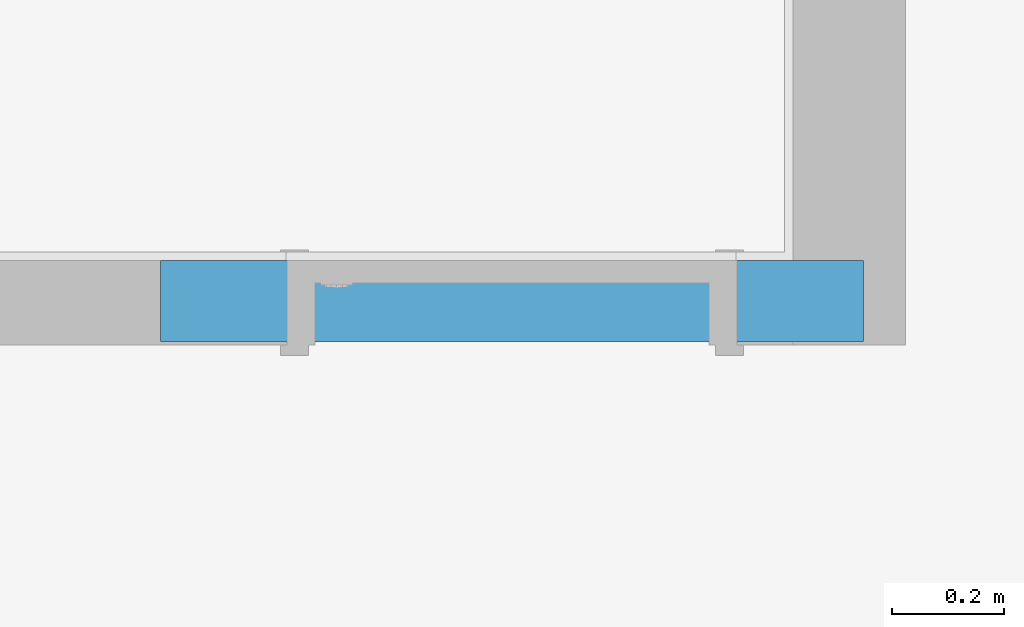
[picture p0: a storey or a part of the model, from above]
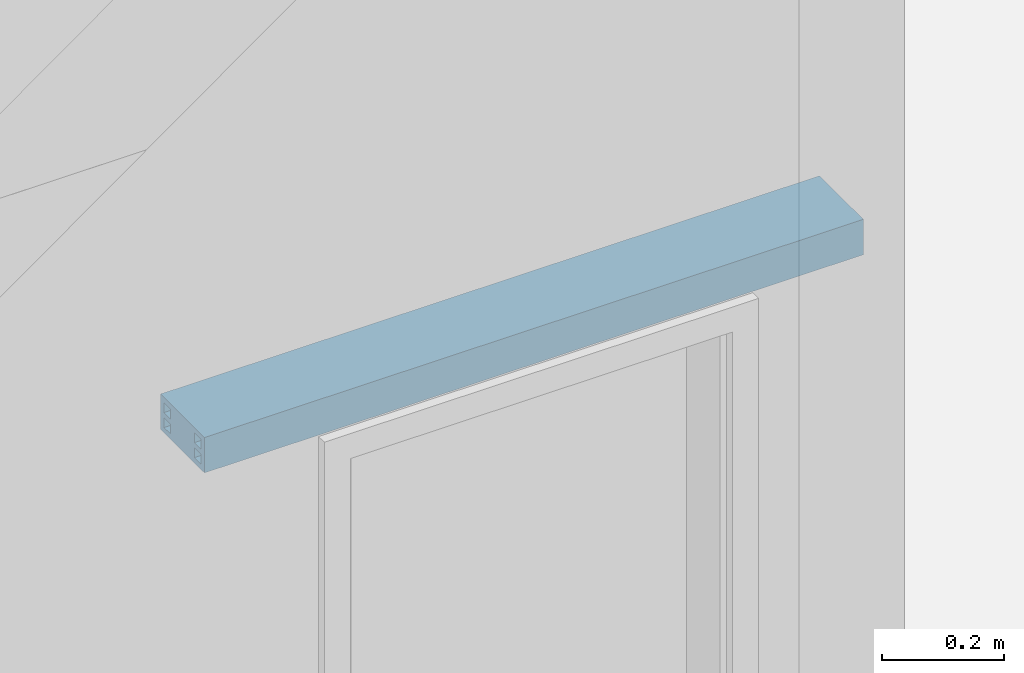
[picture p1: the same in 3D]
Properties of the parts of a building model (IFC4)

# File
Description: ViewDefinition [ReferenceView_V1.2], ExchangeRequirement [Architecture], Option [Elements to export: Visible elements (on all stories)], Option [Partial Structure Display: Entire Model], Option [IFC Domain: All], Option [Structural Function: All Elements], Option [Convert Grid elements: On], Option [Convert IFC Annotations and Archicad 2D elements: Off], Option [Convert 2D symbols of Doors and Windows: Off], Option [Export geometries that Participates in Collision Detection only: On], Option [Split complex elements: Off], Option [Material Preservation: Explode where necessary], Option [IFC Model position: Survey Point and Project Origin], Option [Curtain Wall export mode: Single Element], Option [Railing export mode: Single Element], Option [Stair export mode: Single Element], Option [Properties To Export: All properties], Option [Space containment: On], Option [IFC Domain For Space Containment: All], Option [Geometry to type objects: Off], Option [Element Properties: Off], Option [Building Material Properties: Off], Option [Element Parameters: Off], Option [Component Parameters: Off], Option [IFC Base Quantities: On], Option [Door Window Parameters: On], Option [IFC Space boundaries: On], Option [Archicad Zone Categories as IFC Space classification data: Off], Option [Element Classifications: Off]
File name: C:\Users\micel\OneDrive\Dokumenty\ŠKOLA\!!4.LS!!\BAKALÁŘKA\Publikace\Nová složka\LES24-PST-ZZ-M3-Nenosne_kce_podlahy.ifc
Time: 2024-05-22T15:32:19
Author: Architect
Organization: Building Designer Office
Written by: DDS_IFC v3.0
Made in: IFC file generated by Graphisoft Archicad 27.0.0 CZE FULL Windows version (IFC add-on version: 3001 CZE FULL).
Authorization: The authorising person

# IfcProject, Univerzitní lezecké centrum
Description: BIM projekt - bakalářská práce

# IfcSite, Exteriér
RefLatitude: 50, 1, 18, 339575; RefLongitude: 15, 46, 11, 568244; RefElevation: 221783 mm
Qto_SiteBaseQuantities - GrossPerimeter: 0 mm; GrossArea: 3562 m2

# IfcBuilding, Univerzitní lezecké centrum
Qto_BuildingBaseQuantities - GrossFloorArea: 0 m2

# IfcBuildingStorey (5)
In: Univerzitní lezecké centrum
Qto_BuildingStoreyBaseQuantities - GrossFloorArea: 0 m2
Name | Elevation (mm) | NetHeight (mm) = GrossHeight (mm)
2.NP | 3200 | 3200
4.NP | 9600 | 3200
1.NP | 0 | 3200
1.PP | -3350 | 3350
3.NP | 6400 | 3200

# IfcBeam: PTH Překlad KP 11,5 a 14,5 (15)
Type - PredefinedType: BEAM
Pset_BeamCommon - Status: EXISTING
Pset_ManufacturerOccurrence - AcquisitionDate: DD.MM.RRRR
Name | In | IsExternal | LoadBearing
2 x Pk02 | 1.PP
3 x Pk01 | 1.PP
Pk01 | 1.NP
2 x Pk02 | 2.NP | no | yes
6 x Pk01 | 2.NP | no | yes
Pk01 | 4.NP

# IfcBeam: PTH Překlad KP7 (3)
Type - PredefinedType: BEAM
Pset_ManufacturerOccurrence - AcquisitionDate: DD.MM.RRRR
Pset_BeamCommon - Status: EXISTING; LoadBearing: yes
Name | In
2 x Pk03 | 1.PP
Pk03 | 1.NP

# IfcDoor: Dveře 24 (8)
Type - OperationType: SINGLE_SWING_LEFT
Type - Door Lining Properties - LiningThickness: 50 mm; CasingThickness: 50 mm; CasingDepth: 19 mm
Type - Door Panel Properties - Panel 1 - PanelDepth: 40 mm; PanelOperation: SWINGING; PanelWidth: 1; PanelPosition: MIDDLE
Parametry - Kování: Bezpečnostní kování; Lakované - RAL 9007; Zámek - fab vložka, stavitelné panty, klika; Typ zárubně: Obložková zárubeň, RAL 6019; Prosklení: Plné (bez prosklení); Materiál dveřního křídla: Dřevěné (dýhované), lakované RAL 6019
Pset_DoorCommon - ThermalTransmittance: 0; Status: EXISTING
Pset_ManufacturerOccurrence - AcquisitionDate: DD.MM.RRRR
Name | In | OverallHeight (mm) | OverallWidth (mm) | Požární odolnost | Tloušťka rámu | Height (mm) | Width (mm) | Perimeter (mm) | Area (m2)
D19 | 1.PP | 2020 | 800 | Bez požadavku | 200 | 0 | 0 | 0 | 0
D05 | 1.PP | 2020 | 800 | Bez požadavku | 150 | 2020 | 800 | 5640 | 1.616
D08 | 1.PP | 2020 | 1000 | Bez požadavku | 150 | 2020 | 1000 | 6040 | 2.02
D11 | 1.NP | 2020 | 900 | EI 30 DP1 - C | 200 | 2020 | 900 | 5840 | 1.818
D14 | 2.NP | 2150 | 800 | Bez požadavku | 150 | 0 | 0 | 0 | 0
2 x D05 | 2.NP | 2020 | 800 | Bez požadavku | 150 | 0 | 0 | 0 | 0
D18 | 2.NP | 2020 | 1000 | Bez požadavku | 150 | 2020 | 1000 | 6040 | 2.02

# IfcDoor: Dveře 24 (10)
Type - OperationType: SINGLE_SWING_RIGHT
Type - Door Lining Properties - LiningThickness: 50 mm; CasingThickness: 50 mm; CasingDepth: 19 mm
Type - Door Panel Properties - Panel 1 - PanelDepth: 40 mm; PanelOperation: SWINGING; PanelWidth: 1; PanelPosition: MIDDLE
Parametry - Kování: Bezpečnostní kování; Lakované - RAL 9007; Zámek - fab vložka, stavitelné panty, klika; Typ zárubně: Obložková zárubeň, RAL 6019; Prosklení: Plné (bez prosklení); Materiál dveřního křídla: Dřevěné (dýhované), lakované RAL 6019; Požární odolnost: Bez požadavku
Pset_DoorCommon - ThermalTransmittance: 0; Status: EXISTING
Pset_ManufacturerOccurrence - AcquisitionDate: DD.MM.RRRR
Name | In | OverallHeight (mm) | OverallWidth (mm) | Tloušťka rámu | Height (mm) | Width (mm) | Perimeter (mm) | Area (m2)
D07 | 1.PP | 2020 | 1000 | 150 | 0 | 0 | 0 | 0
2 x D06 | 1.PP | 2020 | 800 | 150 | 0 | 0 | 0 | 0
D20 | 1.PP | 2020 | 800 | 200 | 2020 | 800 | 5640 | 1.616
D06 | 1.NP | 2020 | 800 | 150 | 2020 | 800 | 5640 | 1.616
D17 | 2.NP | 2020 | 1000 | 150 | 2020 | 1000 | 6040 | 2.02
2 x D06 | 2.NP | 2020 | 800 | 150 | 0 | 0 | 0 | 0
D14 | 2.NP | 2150 | 800 | 150 | 2150 | 800 | 5900 | 1.72
D06 | 4.NP | 2020 | 800 | 150 | 2020 | 800 | 5640 | 1.616

# IfcFurniture: Keramické tvárnice nenosné tl. 150 mm 230
In: 1.NP
Description: Deska recepčního pultu; Material: Keramické tvárnice nenosné tl. 150 mm
Pset_ManufacturerOccurrence - AcquisitionDate: DD.MM.RRRR

# IfcOpeningElement (18)
Name | In | Depth (mm) | Height (mm) | Width (mm) | Area (m2) | Volume (m3)
D19 | 1.PP | 200 | 0 | 0 | 0 | 0.111782
D07 | 1.PP | 150 | 0 | 0 | 0 | 0.117572
D06 | 1.PP | 150 | 0 | 0 | 0 | 0.100082
D06 | 1.PP | 150 | 0 | 0 | 0 | 0.0999325
D05 | 1.PP | 150 | 2020 | 800 | 1.616 | 0.0999325
D08 | 1.PP | 150 | 2020 | 1000 | 2.02 | 0.117572
D20 | 1.PP | 200 | 2020 | 800 | 1.616 | 0.111782
D11 | 1.NP | 200 | 2020 | 900 | 1.818 | 0.120852
D06 | 1.NP | 150 | 2020 | 800 | 1.616 | 0.0999325
D17 | 2.NP | 150 | 2020 | 1000 | 2.02 | 0.117572
D14 | 2.NP | 150 | 0 | 0 | 0 | 0.104041
2 x D05 | 2.NP | 150 | 0 | 0 | 0 | 0.0999325
2 x D06 | 2.NP | 150 | 0 | 0 | 0 | 0.0999325
D14 | 2.NP | 150 | 2150 | 800 | 1.72 | 0.104041
D18 | 2.NP | 150 | 2020 | 1000 | 2.02 | 0.117572
D06 | 4.NP | 150 | 2020 | 800 | 1.616 | 0.0999325

# IfcSlab: !Okapový chodník/Terasa/chodník 312
In: 1.NP
Type - PredefinedType: ROOF
Material: Betonová dlažba zámková, Štěrk - frakce 4/8, Štěrk - frakce 8/16, Geotextilie 300 g/m2
Pset_SlabCommon - Status: EXISTING; LoadBearing: yes
Pset_ManufacturerOccurrence - AcquisitionDate: DD.MM.RRRR
Qto_SlabBaseQuantities - Width: 312 mm; Perimeter: 13.8539 mm; GrossArea: 0.00000555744 m2; NetArea: 0.00000555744 m2; GrossVolume: 0.00000173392 m3; NetVolume: 0.00000173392 m3; Betonová dlažba zámková, Width: 60 mm; Štěrk - frakce 4/8, Width: 40 mm; Štěrk - frakce 8/16, Width: 160 mm; Geotextilie 300 g/m2, Width: 2 mm

# IfcSlab: !P01 Podlaha na terénu - keramická dlažba 30x30 220, P01
In: 1.PP
Type - PredefinedType: FLOOR
Material: Keramická dlažba 30x30, Lepicí tmel na dlažbu a obklady, Samonivelační stěrková hmota, Hydroizolace - stěrková hmota, Penetrační nátěr, Betonová mazanina, PE fólie, Tepelná izolace - polystyren EPS podlahy, Hydroizolace - modifikovaný asfaltový pás, Penetrační nátěr asfaltový
Pset_SlabCommon - Status: EXISTING; LoadBearing: yes
Pset_ManufacturerOccurrence - AcquisitionDate: DD.MM.RRRR
Qto_SlabBaseQuantities - Width: 219.5 mm; Perimeter: 58727.6 mm; GrossArea: 144.231 m2; NetArea: 135.277 m2; GrossVolume: 31.8491 m3; NetVolume: 29.8836 m3; Keramická dlažba 30x30, Width: 10 mm; Lepicí tmel na dlažbu a obklady, Width: 3 mm; Samonivelační stěrková hmota, Width: 3 mm; Hydroizolace - stěrková hmota, Width: 2 mm; Penetrační nátěr, Width: 1 mm; Betonová mazanina, Width: 75 mm; PE fólie, Width: 0.5 mm; Tepelná izolace - polystyren EPS podlahy, Width: 120 mm; Hydroizolace - modifikovaný asfaltový pás, Width: 4 mm; Penetrační nátěr asfaltový, Width: 1 mm

# IfcSlab: !P02 Podlaha na terénu - keramická dlažba 60x60 220 (2)
In: 1.PP
Type - PredefinedType: FLOOR
Material: Keramická dlažba 60x60, Lepicí tmel na dlažbu a obklady, Samonivelační stěrková hmota, Hydroizolace - stěrková hmota, Penetrační nátěr, Betonová mazanina, PE fólie, Tepelná izolace - polystyren EPS podlahy, Hydroizolace - modifikovaný asfaltový pás, Penetrační nátěr asfaltový
Pset_ManufacturerOccurrence - AcquisitionDate: DD.MM.RRRR
Pset_SlabCommon - Status: EXISTING
Qto_SlabBaseQuantities - Width: 219.5 mm; Keramická dlažba 60x60, Width: 10 mm; Lepicí tmel na dlažbu a obklady, Width: 3 mm; Samonivelační stěrková hmota, Width: 3 mm; Hydroizolace - stěrková hmota, Width: 2 mm; Penetrační nátěr, Width: 1 mm; Betonová mazanina, Width: 75 mm; PE fólie, Width: 0.5 mm; Tepelná izolace - polystyren EPS podlahy, Width: 120 mm; Hydroizolace - modifikovaný asfaltový pás, Width: 4 mm; Penetrační nátěr asfaltový, Width: 1 mm
Name | Perimeter (mm) | GrossArea (m2) | NetArea (m2) | GrossVolume (m3) | NetVolume (m3)
P02 | 17770.6 | 9.21407 | 8.33584 | 2.02233 | 1.82956 | Pset_SlabCommon - LoadBearing: yes
P02 | 14831.3 | 14.3689 | 14.1468 | 3.15396 | 3.10522 | Pset_SlabCommon - IsExternal: no

# IfcSlab: !P03 Podlaha v patře - keramická dlažba 60x60 120 (4)
Type - PredefinedType: FLOOR
Material: Keramická dlažba 60x60, Lepicí tmel na dlažbu a obklady, Samonivelační stěrková hmota, Betonová mazanina, PE fólie, Akustická izolace - EPS
Pset_SlabCommon - Status: EXISTING; LoadBearing: yes
Pset_ManufacturerOccurrence - AcquisitionDate: DD.MM.RRRR
Qto_SlabBaseQuantities - Width: 119.5 mm; Keramická dlažba 60x60, Width: 10 mm; Lepicí tmel na dlažbu a obklady, Width: 3 mm; Samonivelační stěrková hmota, Width: 3 mm; Betonová mazanina, Width: 63 mm; PE fólie, Width: 0.5 mm; Akustická izolace - EPS, Width: 40 mm
Name | In | Perimeter (mm) | GrossArea (m2) | NetArea (m2) | GrossVolume (m3) | NetVolume (m3)
P03 | 1.NP | 54495.8 | 152.616 | 148.791 | 18.2376 | 17.7806
P03 | 2.NP | 15181.6 | 14.247 | 14.1612 | 1.70252 | 1.69226
P03 | 3.NP | 40740.1 | 31.2389 | 31.2389 | 3.73305 | 3.73304
P03 | 4.NP | 45092.5 | 63.2084 | 62.2234 | 7.55341 | 7.43569

# IfcSlab: !P04 Podlaha v patře - keramická dlažba 30x30 120 (4)
Type - PredefinedType: FLOOR
Material: Keramická dlažba 30x30, Lepicí tmel na dlažbu a obklady, Samonivelační stěrková hmota, Betonová mazanina, PE fólie, Akustická izolace - EPS
Pset_SlabCommon - Status: EXISTING; LoadBearing: yes
Qto_SlabBaseQuantities - Width: 119.5 mm; Keramická dlažba 30x30, Width: 10 mm; Lepicí tmel na dlažbu a obklady, Width: 3 mm; Samonivelační stěrková hmota, Width: 3 mm; Betonová mazanina, Width: 63 mm; PE fólie, Width: 0.5 mm; Akustická izolace - EPS, Width: 40 mm
Pset_ManufacturerOccurrence - AcquisitionDate: DD.MM.RRRR
Name | In | Perimeter (mm) | GrossArea (m2) | NetArea (m2) | GrossVolume (m3) | NetVolume (m3)
P03 | 1.NP | 15785.6 | 12.3424 | 12.3422 | 1.47491 | 1.4749
P03 | 1.NP | 6549.48 | 2.55715 | 2.55715 | 0.305579 | 0.305579
P04 | 2.NP | 21385.9 | 28.0574 | 26.6548 | 3.35286 | 3.18525
P04 | 2.NP | 21415.9 | 28.0724 | 26.6698 | 3.35465 | 3.18704

# IfcSlab: !Podlaha na terénu - polyuretanová stěrka 220, P06
In: 1.PP
Type - PredefinedType: FLOOR
Material: Polyuretanová stěrka - sport, Penetrační nátěr pod polyuretanovou stěrku, Samonivelační stěrková hmota, Betonová mazanina, PE fólie, Tepelná izolace - polystyren EPS podlahy, Hydroizolace - modifikovaný asfaltový pás, Penetrační nátěr asfaltový
Pset_SlabCommon - Status: EXISTING; LoadBearing: yes
Pset_ManufacturerOccurrence - AcquisitionDate: DD.MM.RRRR
Qto_SlabBaseQuantities - Width: 219.5 mm; Perimeter: 51417.3 mm; GrossArea: 156.982 m2; NetArea: 154.317 m2; GrossVolume: 34.4575 m3; NetVolume: 33.8726 m3; Polyuretanová stěrka - sport, Width: 1 mm; Penetrační nátěr pod polyuretanovou stěrku, Width: 1 mm; Samonivelační stěrková hmota, Width: 3 mm; Betonová mazanina, Width: 89 mm; PE fólie, Width: 0.5 mm; Tepelná izolace - polystyren EPS podlahy, Width: 120 mm; Hydroizolace - modifikovaný asfaltový pás, Width: 4 mm; Penetrační nátěr asfaltový, Width: 1 mm

# IfcSlab: !Podlaha v patře - polyuretanová stěrka - sport 120, P05a
In: 2.NP
Type - PredefinedType: FLOOR
Material: Polyuretanová stěrka - sport, Penetrační nátěr pod polyuretanovou stěrku, Samonivelační stěrková hmota, Betonová mazanina, PE fólie, Akustická izolace - EPS
Qto_SlabBaseQuantities - Width: 119.5 mm; Perimeter: 41289.7 mm; GrossArea: 91.0404 m2; NetArea: 89.2593 m2; GrossVolume: 10.8793 m3; NetVolume: 10.6665 m3; Polyuretanová stěrka - sport, Width: 1 mm; Penetrační nátěr pod polyuretanovou stěrku, Width: 1 mm; Samonivelační stěrková hmota, Width: 3 mm; Betonová mazanina, Width: 74 mm; PE fólie, Width: 0.5 mm; Akustická izolace - EPS, Width: 40 mm
Pset_ManufacturerOccurrence - AcquisitionDate: DD.MM.RRRR
Pset_SlabCommon - Status: EXISTING; LoadBearing: yes

# IfcSlab: !Podlaha v patře - polyuretanová stěrka 120 (2)
In: 3.NP
Type - PredefinedType: FLOOR
Material: Polyuretanová stěrka, Penetrační nátěr pod polyuretanovou stěrku, Samonivelační stěrková hmota, Betonová mazanina, PE fólie, Akustická izolace - EPS
Qto_SlabBaseQuantities - Width: 119.5 mm; Polyuretanová stěrka, Width: 1 mm; Penetrační nátěr pod polyuretanovou stěrku, Width: 1 mm; Samonivelační stěrková hmota, Width: 3 mm; Betonová mazanina, Width: 74 mm; PE fólie, Width: 0.5 mm; Akustická izolace - EPS, Width: 40 mm
Pset_SlabCommon - Status: EXISTING; LoadBearing: yes
Pset_ManufacturerOccurrence - AcquisitionDate: DD.MM.RRRR
Name | Perimeter (mm) | GrossArea (m2) | NetArea (m2) | GrossVolume (m3) | NetVolume (m3)
P05b | 18894.6 | 13.0671 | 13.0467 | 2.59749 | 2.59505
P03 | 19786.7 | 23.467 | 23.467 | 2.8043 | 2.8043

# IfcSlab: !SDK - hygienický 90 (11)
Type - PredefinedType: FLOOR
Description: Sádrokartonový podhled - hygienický, SDK desky se zvýšenou odolností do vlhka, na samonosném roštu; Material: SDK - UA profil nosný 50, SDK - R-CD profil montážní, Sádrokarton - voděodolný
Pset_SlabCommon - Status: EXISTING; LoadBearing: yes
Pset_ManufacturerOccurrence - AcquisitionDate: DD.MM.RRRR
Qto_SlabBaseQuantities - Width: 90 mm; SDK - UA profil nosný 50, Width: 50 mm; SDK - R-CD profil montážní, Width: 27 mm; Sádrokarton - voděodolný, Width: 13 mm
Name | In | Perimeter (mm) | GrossArea (m2) | NetArea (m2) | GrossVolume (m3) | NetVolume (m3)
Pdh01 | 1.PP | 15699.4 | 9.41867 | 9.41867 | 0.84768 | 0.84768
2 x Pdh01 | 1.PP | 14299.5 | 11.9238 | 11.9238 | 1.07314 | 1.07314
Pdh01 | 1.PP | 15856.7 | 9.53889 | 9.4189 | 0.8585 | 0.847701
Pdh01 | 1.PP | 7099.48 | 3.14456 | 2.58964 | 0.327404 | 0.277461
2 x Pdh01 | 2.NP | 8009.59 | 3.99911 | 3.98961 | 0.35992 | 0.359065
Pdh01 | 2.NP | 6099.58 | 1.99479 | 1.99468 | 0.179531 | 0.179521
Pdh01 | 2.NP | 8699.04 | 4.72396 | 4.09391 | 0.425157 | 0.368452
Pdh01 | 2.NP | 6099.58 | 1.99479 | 1.99464 | 0.179531 | 0.179518
Pdh01 | 2.NP | 8699 | 4.72391 | 4.09383 | 0.425152 | 0.368445

# IfcSlab: !SDK - protipožární 152 (2)
In: 4.NP
Type - PredefinedType: FLOOR
Description: Sádrokartonový podhled - protipožární, SDK deska se zvýšenou odolností a stabilitou při požáru, na samonosném roštu; Material: SDK - UA profil nosný 50, SDK - R-CD profil montážní, Sádrokarton - protipožární spodní, Sádrokarton - protipožární vrchní
Pset_SlabCommon - Status: EXISTING; LoadBearing: yes
Pset_ManufacturerOccurrence - AcquisitionDate: DD.MM.RRRR
Qto_SlabBaseQuantities - Width: 152 mm; SDK - UA profil nosný 50, Width: 100 mm; SDK - R-CD profil montážní, Width: 27 mm; Sádrokarton - protipožární spodní, Width: 12 mm; Sádrokarton - protipožární vrchní, Width: 13 mm
Name | Perimeter (mm) | GrossArea (m2) | NetArea (m2) | GrossVolume (m3) | NetVolume (m3)
Pdh02 | 19786.3 | 23.2636 | 22.7836 | 3.53606 | 3.46311
Pdh02 | 19786.4 | 24.0737 | 24.0737 | 3.65921 | 3.65921

# IfcSlab: Beton zákad pod technická zařízení 150 (2)
In: 3.NP
Type - PredefinedType: FLOOR
Description: Betonový základ pro technologii ohřevu vody; Material: Beton zákad pod technická zařízení
Pset_SlabCommon - IsExternal: no; Status: EXISTING
Pset_ManufacturerOccurrence - AcquisitionDate: DD.MM.RRRR
Qto_SlabBaseQuantities - Width: 150 mm; Beton zákad pod technická zařízení, Width: 150 mm
Name | Perimeter (mm) | GrossArea (m2) = NetArea (m2) | GrossVolume (m3) = NetVolume (m3)
 | 12933.8 | 7.32782 | 1.09917
 | 5900 | 1.72 | 0.258

# IfcSlab: Keramická dlažba 20x40 - obklad 1500 (3)
Type - PredefinedType: FLOOR
Description: Keramický obklad, lepeno stavebním lepidlem, součástí skladeb přilehlých svislých konstrukcí; Material: Keramická dlažba 20x40 - obklad
Pset_SlabCommon - IsExternal: no; Status: EXISTING
Qto_SlabBaseQuantities - Width: 1500 mm; Keramická dlažba 20x40 - obklad, Width: 1500 mm
Pset_ManufacturerOccurrence - AcquisitionDate: DD.MM.RRRR
Name | In | Perimeter (mm) | GrossArea (m2) = NetArea (m2) | GrossVolume (m3) = NetVolume (m3)
 | 1.PP | 11906.6 | 0.0890746 | 0.133612
 | 1.NP | 11109 | 0.0830922 | 0.124638
 | 4.NP | 10509 | 0.0785922 | 0.117888

# IfcSlab: Keramická dlažba 20x40 - obklad 175 (2)
In: 2.NP
Type - PredefinedType: FLOOR
Description: Keramický obklad, lepeno stavebním lepidlem, součástí skladeb přilehlých svislých konstrukcí; Material: Keramická dlažba 20x40 - obklad
Pset_ManufacturerOccurrence - AcquisitionDate: DD.MM.RRRR
Qto_SlabBaseQuantities - Width: 175 mm; Perimeter: 1630 mm; GrossArea: 0.012 m2; NetArea: 0.012 m2; GrossVolume: 0.0021 m3; NetVolume: 0.0021 m3; Keramická dlažba 20x40 - obklad, Width: 175 mm
Pset_SlabCommon - IsExternal: no; Status: EXISTING

# IfcSlab: Keramická dlažba 20x40 - obklad 2300 (10)
Type - PredefinedType: FLOOR
Description: Keramický obklad, lepeno stavebním lepidlem, součástí skladeb přilehlých svislých konstrukcí; Material: Keramická dlažba 20x40 - obklad
Pset_SlabCommon - IsExternal: no; Status: EXISTING
Pset_ManufacturerOccurrence - AcquisitionDate: DD.MM.RRRR
Qto_SlabBaseQuantities - Width: 2300 mm; Keramická dlažba 20x40 - obklad, Width: 2300 mm
Name | In | Perimeter (mm) | GrossArea (m2) = NetArea (m2) | GrossVolume (m3) = NetVolume (m3)
2 x  | 1.PP | 29708.1 | 0.22261 | 0.512002
2 x  | 2.NP | 6669.2 | 0.049794 | 0.114526
2 x  | 2.NP | 349.985 | 0.00239989 | 0.00551975
2 x  | 2.NP | 15708.4 | 0.116827 | 0.268702
2 x  | 2.NP | 350 | 0.0024 | 0.00552

# IfcSlab: Keramická dlažba 20x40 - obklad 2600 (4)
Type - PredefinedType: FLOOR
Description: Keramický obklad, lepeno stavebním lepidlem, součástí skladeb přilehlých svislých konstrukcí; Material: Keramická dlažba 20x40 - obklad
Pset_ManufacturerOccurrence - AcquisitionDate: DD.MM.RRRR
Pset_SlabCommon - IsExternal: no; Status: EXISTING
Qto_SlabBaseQuantities - Width: 2600 mm; Keramická dlažba 20x40 - obklad, Width: 2600 mm
Name | In | Perimeter (mm) | GrossArea (m2) = NetArea (m2) | GrossVolume (m3) = NetVolume (m3)
2 x  | 1.PP | 26909 | 0.201592 | 0.52414
2 x  | 2.NP | 14309.2 | 0.107109 | 0.278484

# IfcSlab: Keramická dlažba 20x40 - obklad 275 (6)
In: 2.NP
Type - PredefinedType: FLOOR
Description: Keramický obklad, lepeno stavebním lepidlem, součástí skladeb přilehlých svislých konstrukcí; Material: Keramická dlažba 20x40 - obklad
Pset_SlabCommon - IsExternal: no; Status: EXISTING
Pset_ManufacturerOccurrence - AcquisitionDate: DD.MM.RRRR
Qto_SlabBaseQuantities - Width: 275 mm; Perimeter: 1630 mm; GrossArea: 0.012 m2; NetArea: 0.012 m2; GrossVolume: 0.0033 m3; NetVolume: 0.0033 m3; Keramická dlažba 20x40 - obklad, Width: 275 mm

# IfcSlab: Keramická dlažba 20x40 - obklad 300 (2)
In: 1.PP
Type - PredefinedType: FLOOR
Description: Keramický obklad, lepeno stavebním lepidlem, součástí skladeb přilehlých svislých konstrukcí; Material: Keramická dlažba 20x40 - obklad
Pset_ManufacturerOccurrence - AcquisitionDate: DD.MM.RRRR
Qto_SlabBaseQuantities - Width: 300 mm; Perimeter: 1630 mm; GrossArea: 0.012 m2; NetArea: 0.012 m2; GrossVolume: 0.0036 m3; NetVolume: 0.0036 m3; Keramická dlažba 20x40 - obklad, Width: 300 mm
Pset_SlabCommon - IsExternal: no; Status: EXISTING

# IfcSlab: Keramická dlažba 20x40 - obklad 575 (2)
In: 2.NP
Type - PredefinedType: FLOOR
Description: Keramický obklad, lepeno stavebním lepidlem, součástí skladeb přilehlých svislých konstrukcí; Material: Keramická dlažba 20x40 - obklad
Pset_SlabCommon - IsExternal: no; Status: EXISTING
Pset_ManufacturerOccurrence - AcquisitionDate: DD.MM.RRRR
Qto_SlabBaseQuantities - Width: 575 mm; Perimeter: 1630 mm; GrossArea: 0.012 m2; NetArea: 0.012 m2; GrossVolume: 0.0069 m3; NetVolume: 0.0069 m3; Keramická dlažba 20x40 - obklad, Width: 575 mm

# IfcSlab: Keramická dlažba 20x40 - obklad 600 (2)
In: 1.PP
Type - PredefinedType: FLOOR
Description: Keramický obklad, lepeno stavebním lepidlem, součástí skladeb přilehlých svislých konstrukcí; Material: Keramická dlažba 20x40 - obklad
Pset_SlabCommon - IsExternal: no; Status: EXISTING
Pset_ManufacturerOccurrence - AcquisitionDate: DD.MM.RRRR
Qto_SlabBaseQuantities - Width: 600 mm; Perimeter: 1630 mm; GrossArea: 0.012 m2; NetArea: 0.012 m2; GrossVolume: 0.0072 m3; NetVolume: 0.0072 m3; Keramická dlažba 20x40 - obklad, Width: 600 mm

# IfcWall: !Vnitřní keramická stěna 150 mm - nenosná 150 (12)
Description: Nenosné broušené keramické tvárnice, 497x140x249 mm, prováděno na maltu pro tenké spáry Profi; Material: Keramické tvárnice nenosné tl. 150 mm
Pset_WallCommon - Status: EXISTING; LoadBearing: yes
Pset_ManufacturerOccurrence - AcquisitionDate: DD.MM.RRRR
Qto_WallBaseQuantities - Width: 150 mm; GrossSideArea: 0 m2; NetSideArea: 0 m2; Keramické tvárnice nenosné tl. 150 mm, Width: 150 mm
Name | In | Length (mm) | Height (mm) | GrossFootprintArea (m2) = NetFootprintArea (m2) | GrossVolume (m3) | NetVolume (m3)
2 x St07 | 1.PP | 1950.16 | 3250 | 0.142524 | 0.940088 | 0.604088
Z061 | 1.PP | 1197.75 | 3250 | 0.0598379 | 0.574549 | 0.305749
Z061 | 1.PP | 5452.48 | 3186.65 | 0.791632 | 1.35927 | 1.35927
St07 | 2.NP | 395.988 | 3000 | 0.0594945 | 0.178484 | 0.178484
St07 | 2.NP | 3100.15 | 3000 | 0.300022 | 1.33945 | 1.01845
St07 | 2.NP | 3100.15 | 3000 | 0.450022 | 1.35007 | 1.02914
St07 | 2.NP | 396.03 | 3000 | 0.0595096 | 0.178529 | 0.178529
St07 | 3.NP | 375 | 3000 | 0.0675 | 0.2025 | 0.2025
St07 | 3.NP | 4400 | 3000 | 0.66 | 1.98 | 1.98
St07 | 3.NP | 1275 | 3000 | 0.18 | 0.54 | 0.54
St07 | 4.NP | 450 | 3577.84 | 0.0675 | 0.240428 | 0.240428

# IfcWall: !Vnitřní keramická stěna 150 mm - nenosná s omítkou 150 (6)
Description: Nenosné broušené keramické tvárnice, 497x140x249 mm, prováděno na maltu pro tenké spáry Profi; Material: Keramické tvárnice nenosné tl. 150 mm
Pset_WallCommon - Status: EXISTING; LoadBearing: yes
Pset_ManufacturerOccurrence - AcquisitionDate: DD.MM.RRRR
Qto_WallBaseQuantities - Width: 150 mm; Keramické tvárnice nenosné tl. 150 mm, Width: 150 mm
Name | In | Length (mm) | Height (mm) | GrossFootprintArea (m2) = NetFootprintArea (m2) | GrossSideArea (m2) = NetSideArea (m2) | GrossVolume (m3) = NetVolume (m3)
St08* | 1.PP | 1850 | 3250 | 0.255 | 2.7625 | 0.82875
St07 | 1.NP | 1524.98 | 2950 | 0.240001 | 2.077 | 0.623102
St07 | 1.NP | 1800.5 | 230 | 0.000935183 | 0 | 0.000215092
St07 | 1.NP | 374.872 | 2950 | 0.0449807 | 0.442318 | 0.132693
St08* | 2.NP | 2099.8 | 3000 | 0.314969 | 3.14969 | 0.944909
St08* | 2.NP | 2099.8 | 3000 | 0.314969 | 3.14969 | 0.944908

# IfcWall: !Vnitřní keramická stěna 150 mm - nenosná* 150 (13)
Description: Nenosné broušené keramické tvárnice, 497x140x249 mm, prováděno na maltu pro tenké spáry Profi; Material: Keramické tvárnice nenosné tl. 150 mm
Pset_WallCommon - Status: EXISTING; LoadBearing: yes
Pset_ManufacturerOccurrence - AcquisitionDate: DD.MM.RRRR
Qto_WallBaseQuantities - Width: 150 mm; GrossSideArea: 0 m2; NetSideArea: 0 m2; Keramické tvárnice nenosné tl. 150 mm, Width: 150 mm
Name | In | Length (mm) | Height (mm) | GrossFootprintArea (m2) = NetFootprintArea (m2) | GrossVolume (m3) | NetVolume (m3)
St07* | 1.PP | 2705.12 | 3250 | 0.270911 | 1.26091 | 0.992112
2 x St07* | 1.PP | 2074.74 | 3250 | 0.299961 | 0.974873 | 0.974873
St07* | 1.PP | 2605.12 | 3250 | 0.270861 | 1.26075 | 0.991947
St07* | 1.PP | 4310.84 | 3250 | 0.647349 | 2.09038 | 2.09038
St07* | 1.PP | 4385.84 | 3250 | 0.669801 | 2.16335 | 2.16335
St07* | 1.NP | 1450 | 2950 | 0.1425 | 0.587397 | 0.330627
St07* | 2.NP | 5549.61 | 3000 | 0.809942 | 2.41723 | 2.41723
St07* | 2.NP | 5549.61 | 3000 | 0.809942 | 2.41633 | 2.41633
St07* | 2.NP | 5549.61 | 3000 | 0.712442 | 2.47321 | 2.20279
St07* | 2.NP | 5549.61 | 3000 | 0.712442 | 2.47411 | 2.20369
St07* | 4.NP | 1275 | 3832.9 | 0.2025 | 0.736494 | 0.479754
St07* | 4.NP | 2074.74 | 3577.84 | 0.299961 | 1.06843 | 1.06843

# IfcWall: !Vnitřní keramická stěna 150 mm - nenosná** 150 (8)
Description: Nenosné broušené keramické tvárnice, 497x140x249 mm, prováděno na maltu pro tenké spáry Profi; Material: Keramické tvárnice nenosné tl. 150 mm
Pset_WallCommon - Status: EXISTING; LoadBearing: yes
Pset_ManufacturerOccurrence - AcquisitionDate: DD.MM.RRRR
Qto_WallBaseQuantities - Width: 150 mm; GrossSideArea: 0 m2; NetSideArea: 0 m2; Keramické tvárnice nenosné tl. 150 mm, Width: 150 mm
Name | In | Length (mm) | Height (mm) | GrossFootprintArea (m2) = NetFootprintArea (m2) | GrossVolume (m3) | NetVolume (m3)
2 x St07** | 1.PP | 1674.99 | 3250 | 0.2625 | 0.85312 | 0.85312
St07** | 1.PP | 2724.74 | 3250 | 0.397461 | 1.29175 | 1.29175
St07** | 1.PP | 2874.74 | 3250 | 0.442461 | 1.438 | 1.438
2 x St07** | 2.NP | 2249.9 | 3000 | 0.217486 | 1.0029 | 0.746103
2 x St07** | 2.NP | 2099.8 | 3000 | 0.194969 | 0.935355 | 0.678555

# IfcWall: !Vnitřní keramická stěna 200 mm - nenosná 200 (3)
Description: Nenosné broušené keramické tvárnice, 372x190x238 mm, prováděno na maltu M10; Material: Keramické tvárnice nenosné tl 200 mm
Pset_WallCommon - Status: EXISTING
Qto_WallBaseQuantities - Width: 200 mm; GrossSideArea: 0 m2; NetSideArea: 0 m2; Keramické tvárnice nenosné tl 200 mm, Width: 200 mm
Pset_ManufacturerOccurrence - AcquisitionDate: DD.MM.RRRR
Name | In | Length (mm) | Height (mm) | GrossFootprintArea (m2) = NetFootprintArea (m2) | GrossVolume (m3) | NetVolume (m3) | LoadBearing
St06 | 1.NP | 5549.82 | 2830 | 0.929967 | 3.14121 | 2.77761
St06 | 2.NP | 925.449 | 3000 | 0.200086 | 0.600198 | 0.600198 | yes
St06 | 2.NP | 925.448 | 3000 | 0.199886 | 0.599657 | 0.599657 | yes

# IfcWall: !Vnitřní keramická stěna 200 mm - nenosná* 200 (3)
Description: Nenosné broušené keramické tvárnice, 372x190x238 mm, prováděno na maltu M10; Material: Keramické tvárnice nenosné tl 200 mm
Pset_WallCommon - Status: EXISTING; LoadBearing: yes
Pset_ManufacturerOccurrence - AcquisitionDate: DD.MM.RRRR
Qto_WallBaseQuantities - Width: 200 mm; GrossSideArea: 0 m2; NetSideArea: 0 m2; Keramické tvárnice nenosné tl 200 mm, Width: 200 mm
Name | In | Length (mm) | Height (mm) | GrossFootprintArea (m2) = NetFootprintArea (m2) | GrossVolume (m3) | NetVolume (m3)
St06* | 1.PP | 8175 | 3250 | 1.49 | 5.29398 | 4.93558
St06* | 1.PP | 8250 | 3250 | 1.49 | 5.29398 | 4.93558
St06* | 1.NP | 1999.74 | 2950 | 0.429948 | 1.26835 | 1.26835

# IfcWall: !Vnitřní pŕobetonová stěna 200 mm - nenosná 200, St09
In: 4.NP
Description: Pŕobetonové tvárnice nenosné, na stavební lepidlo; Material: Pórobetonové tvárnice - nenosné
Pset_WallCommon - Status: EXISTING; LoadBearing: yes
Pset_ManufacturerOccurrence - AcquisitionDate: DD.MM.RRRR
Qto_WallBaseQuantities - Length: 6114.95 mm; Height: 1228.24 mm; Width: 200 mm; GrossFootprintArea: 1.22341 m2; NetFootprintArea: 1.22341 m2; GrossSideArea: 3.11455 m2; NetSideArea: 3.11455 m2; GrossVolume: 1.33133 m3; NetVolume: 1.33133 m3; Pórobetonové tvárnice - nenosné, Width: 200 mm

# IfcWall: Keramické tvárnice nenosné tl. 150 mm 150 (8)
Description: Nenosné broušené keramické tvárnice, 497x140x249 mm, prováděno na maltu pro tenké spáry Profi; Material: Keramické tvárnice nenosné tl. 150 mm
Pset_WallCommon - Status: EXISTING; LoadBearing: yes
Qto_WallBaseQuantities - Width: 150 mm; Keramické tvárnice nenosné tl. 150 mm, Width: 150 mm
Pset_ManufacturerOccurrence - AcquisitionDate: DD.MM.RRRR
Name | In | Length (mm) | Height (mm) | GrossFootprintArea (m2) = NetFootprintArea (m2) | GrossSideArea (m2) = NetSideArea (m2) | GrossVolume (m3) = NetVolume (m3)
 | 1.PP | 600 | 3250 | 0.09 | 1.95 | 0.2925
2 x St08 | 1.PP | 3450 | 3250 | 0.5175 | 11.2125 | 1.68188
 | 1.PP | 450 | 3250 | 0.0675 | 1.4625 | 0.219375
St08 | 1.NP | 1350 | 2950 | 0.2025 | 3.9825 | 0.597375
St07 | 1.NP | 3050 | 2950 | 0.4575 | 8.9975 | 1.34963
Z062 | 4.NP | 1200 | 712.904 | 0.18 | 0.702444 | 0.105367
St08 | 4.NP | 1200 | 3120 | 0.18 | 3.744 | 0.5616

# IfcWall: Pórobetonové tvárnice - nenosné 150, Z061
In: 1.PP
Description: Pŕobetonové tvárnice nenosné, na stavební lepidlo; Material: Pórobetonové tvárnice - nenosné
Pset_ManufacturerOccurrence - AcquisitionDate: DD.MM.RRRR
Qto_WallBaseQuantities - Length: 1194.21 mm; Height: 1862.5 mm; Width: 150 mm; GrossFootprintArea: 0.156769 m2; NetFootprintArea: 0.156769 m2; GrossSideArea: 1.71622 m2; NetSideArea: 1.71622 m2; GrossVolume: 0.257729 m3; NetVolume: 0.257729 m3; Pórobetonové tvárnice - nenosné, Width: 150 mm
Pset_WallCommon - Status: EXISTING; LoadBearing: yes

# IfcWall: Pórobetonové tvárnice - nenosné 300
In: 4.NP
Description: Pŕobetonové tvárnice nenosné, na stavební lepidlo; Material: Pórobetonové tvárnice - nenosné
Pset_ManufacturerOccurrence - AcquisitionDate: DD.MM.RRRR
Qto_WallBaseQuantities - Length: 5120 mm; Height: 267.655 mm; Width: 300 mm; GrossFootprintArea: 1.536 m2; NetFootprintArea: 1.536 m2; GrossSideArea: 1.20715 m2; NetSideArea: 1.20715 m2; GrossVolume: 0.362145 m3; NetVolume: 0.362145 m3; Pórobetonové tvárnice - nenosné, Width: 300 mm
Pset_WallCommon - Status: EXISTING; LoadBearing: yes

# IfcWall: SDK - instalační předstěna 150 (8)
Description: Instalační předstěna z dvojitého SDK opláštění, na hliníkovém roštu, SDk se zvýšenou odolností do vlhka
Pset_WallCommon - Status: EXISTING; LoadBearing: yes
Pset_ManufacturerOccurrence - AcquisitionDate: DD.MM.RRRR
Qto_WallBaseQuantities - Width: 150 mm; Keramická dlažba 20x40 - obklad, Width: 7 mm; Lepicí tmel na dlažbu a obklady, Width: 3 mm; SDK nosný rám, Width: 115 mm
Name | In | Material | Length (mm) | Height (mm) | GrossFootprintArea (m2) = NetFootprintArea (m2) | GrossSideArea (m2) = NetSideArea (m2) | GrossVolume (m3) = NetVolume (m3) | Sádrokarton - voděodolný 1, Width (mm) | Sádrokarton - voděodolný 2, Width (mm)
St08 | 1.PP | Keramická dlažba 20x40 - obklad, Lepicí tmel na dlažbu a obklady, Sádrokarton - voděodolný (2), SDK nosný rám | 2174.76 | 3049 | 0.314963 | 6.38221 | 0.959673 | 13 | 12
St08 | 1.PP | SDK nosný rám, Sádrokarton - voděodolný (2), Lepicí tmel na dlažbu a obklady, Keramická dlažba 20x40 - obklad | 2174.76 | 3049 | 0.314963 | 6.38221 | 0.959673 | 12 | 13
St08 | 1.PP | Keramická dlažba 20x40 - obklad, Lepicí tmel na dlažbu a obklady, Sádrokarton - voděodolný (2), SDK nosný rám | 1200.24 | 3049 | 0.180037 | 3.64814 | 0.548559 | 13 | 12
St08 | 1.PP | SDK nosný rám, Sádrokarton - voděodolný (2), Lepicí tmel na dlažbu a obklady, Keramická dlažba 20x40 - obklad | 1275.24 | 3049 | 0.180037 | 3.64814 | 0.548559 | 12 | 13
St08 | 1.NP | SDK nosný rám, Sádrokarton - voděodolný (2), Lepicí tmel na dlažbu a obklady, Keramická dlažba 20x40 - obklad | 1450 | 2950 | 0.2025 | 3.9825 | 0.597375 | 12 | 13
2 x St08* | 2.NP | Keramická dlažba 20x40 - obklad, Lepicí tmel na dlažbu a obklady, Sádrokarton - voděodolný (2), SDK nosný rám | 2099.8 | 3000 | 0.314969 | 6.17393 | 0.943152 | 13 | 12
St08 | 4.NP | Keramická dlažba 20x40 - obklad, Lepicí tmel na dlažbu a obklady, Sádrokarton - voděodolný (2), SDK nosný rám | 1200 | 3100 | 0.18 | 3.72 | 0.558 | 13 | 12

# IfcWall: SDK - instalační předstěna* 150, St08*
In: 1.PP
Description: Instalační předstěna z dvojitého SDK opláštění, na hliníkovém roštu, SDk se zvýšenou odolností do vlhka; Material: SDK nosný rám, Sádrokarton - voděodolný (2), Lepicí tmel na dlažbu a obklady, Keramická dlažba 20x40 - obklad
Qto_WallBaseQuantities - Length: 1700 mm; Height: 3030 mm; Width: 150 mm; GrossFootprintArea: 0.255 m2; NetFootprintArea: 0.255 m2; GrossSideArea: 5.046 m2; NetSideArea: 5.046 m2; GrossVolume: 0.7569 m3; NetVolume: 0.7569 m3; Keramická dlažba 20x40 - obklad, Width: 7 mm; Lepicí tmel na dlažbu a obklady, Width: 3 mm; Sádrokarton - voděodolný 2, Width: 13 mm; Sádrokarton - voděodolný 1, Width: 12 mm; SDK nosný rám, Width: 115 mm
Pset_WallCommon - Status: EXISTING; LoadBearing: yes
Pset_ManufacturerOccurrence - AcquisitionDate: DD.MM.RRRR
